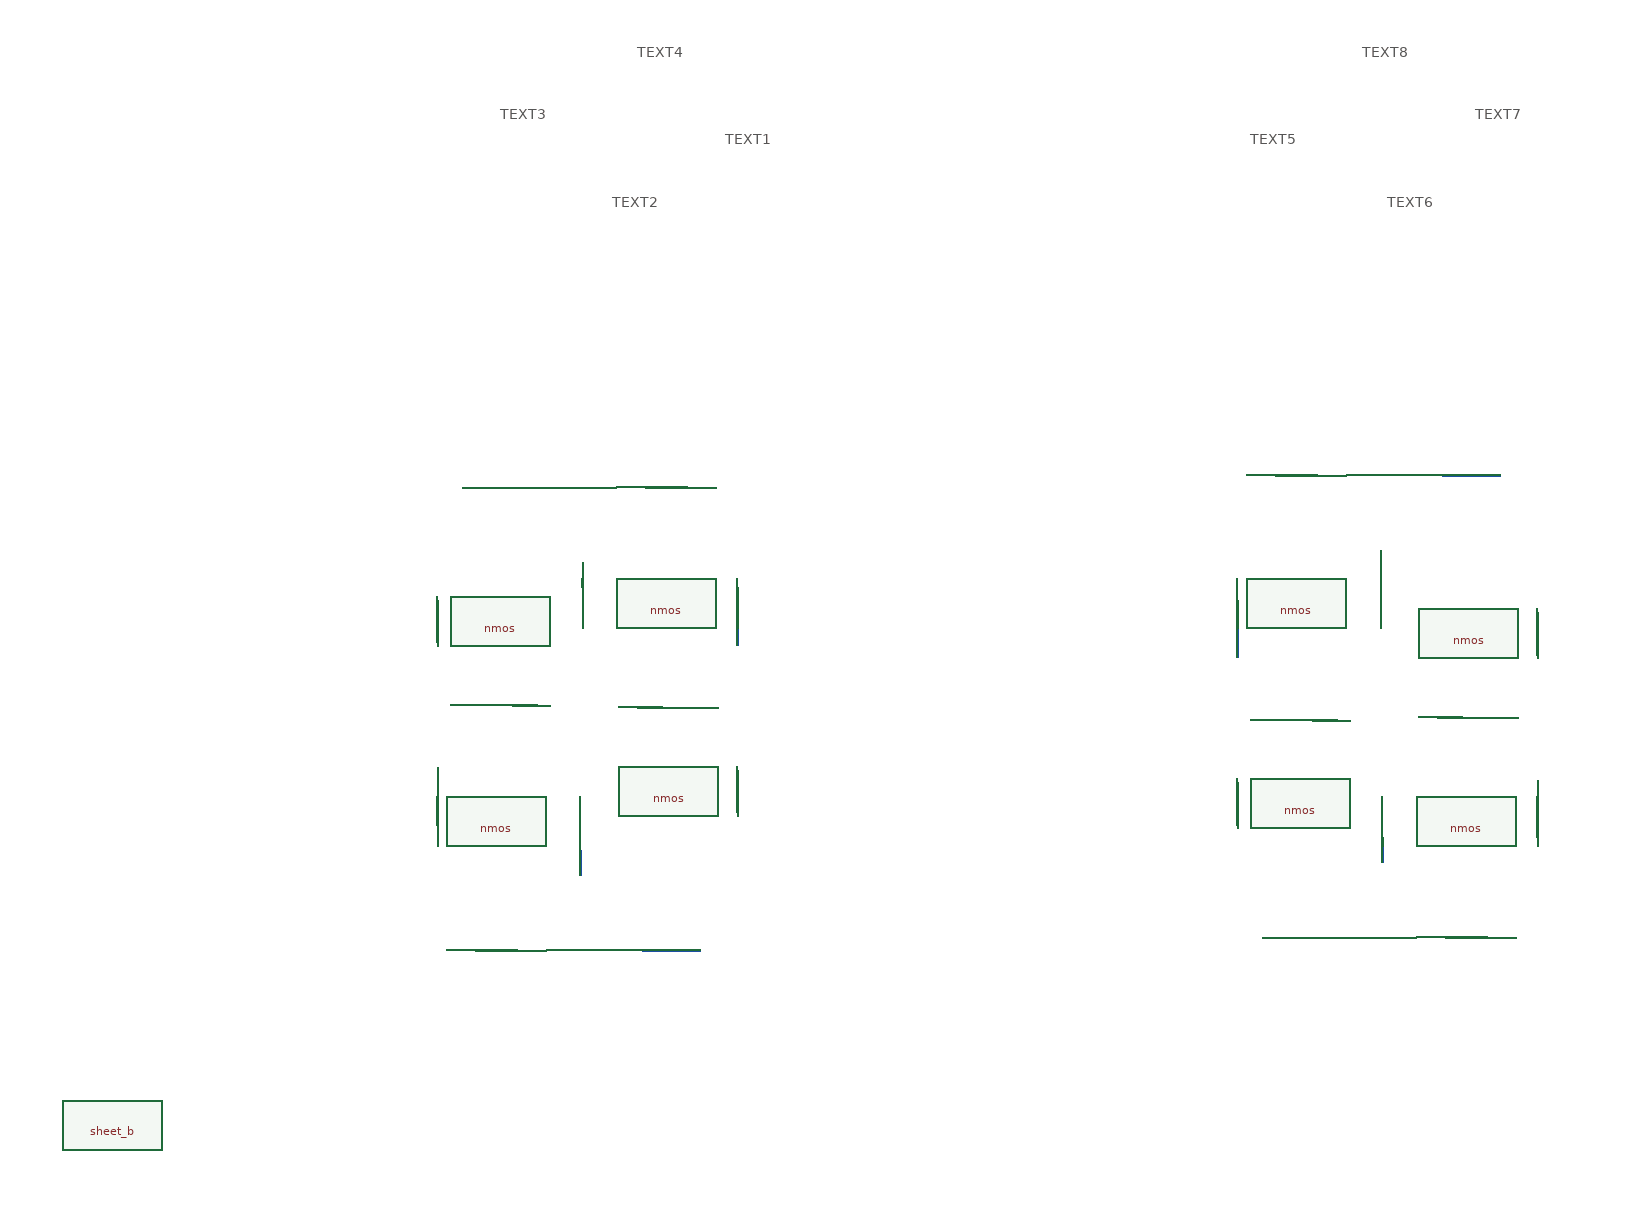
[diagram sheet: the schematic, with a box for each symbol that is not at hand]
v {xschem version=3.0.0 file_version=1.2 }
G {}
K {}
V {}
S {}
E {}
T {TEXT1} 490 -800 2 1 0.333333 0.333333 {  }
T {TEXT2} 400 -750 3 1 0.333333 0.333333 {  }
T {TEXT3} 310 -820 0 1 0.333333 0.333333 {  }
T {TEXT4} 420 -870 1 1 0.333333 0.333333 {  }
T {TEXT7} 1090 -820 0 0 0.333333 0.333333 {  }
T {TEXT6} 1020 -750 1 0 0.333333 0.333333 {  }
T {TEXT5} 910 -800 2 0 0.333333 0.333333 {  }
T {TEXT8} 1000 -870 3 0 0.333333 0.333333 {  }
N 930 -520 964 -520 {}
N 1064 -520 1110 -520 {}
N 1014 -460 1014 -440 {}
N 1066 -150 1100 -150 {}
N 920 -150 966 -150 {}
N 1016 -230 1016 -210 {}
N 900 -274 900 -240 {}
N 900 -420 900 -374 {}
N 960 -324 980 -324 {}
N 1140 -410 1140 -376 {}
N 1140 -276 1140 -230 {}
N 1060 -326 1080 -326 {}
N 290 -140 324 -140 {}
N 424 -140 470 -140 {}
N 374 -220 374 -200 {}
N 426 -510 460 -510 {}
N 280 -510 326 -510 {}
N 376 -450 376 -430 {}
N 260 -420 260 -386 {}
N 260 -286 260 -240 {}
N 320 -336 340 -336 {}
N 500 -284 500 -250 {}
N 500 -430 500 -384 {}
N 420 -334 440 -334 {}
C {xschem_lib/nmos.sym} 964 -460 1 1 {}
C {xschem_lib/nmos.sym} 1066 -210 3 1 {}
C {xschem_lib/nmos.sym} 960 -274 0 1 {}
C {xschem_lib/nmos.sym} 1080 -376 2 1 {}
C {xschem_lib/nmos.sym} 324 -200 1 0 {}
C {xschem_lib/nmos.sym} 426 -450 3 0 {}
C {xschem_lib/nmos.sym} 320 -386 2 0 {}
C {xschem_lib/sheet_b.sym} 0 0 0 0 {}
C {xschem_lib/nmos.sym} 440 -284 0 0 {}
